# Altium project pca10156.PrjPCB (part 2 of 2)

## Sheet pca10156_sheet7_connectors.SchDoc: =BoardTitle+' - Connectors'
size A3; Organization: Nordic Semiconductor; DocumentNumber: 7; Revision: 0.9.1; SheetNumber: 7; SheetTotal: 7; Author: STL1; CompanyName: Nordic Semiconductor; DrawnBy: STL1; DocumentSize: A4

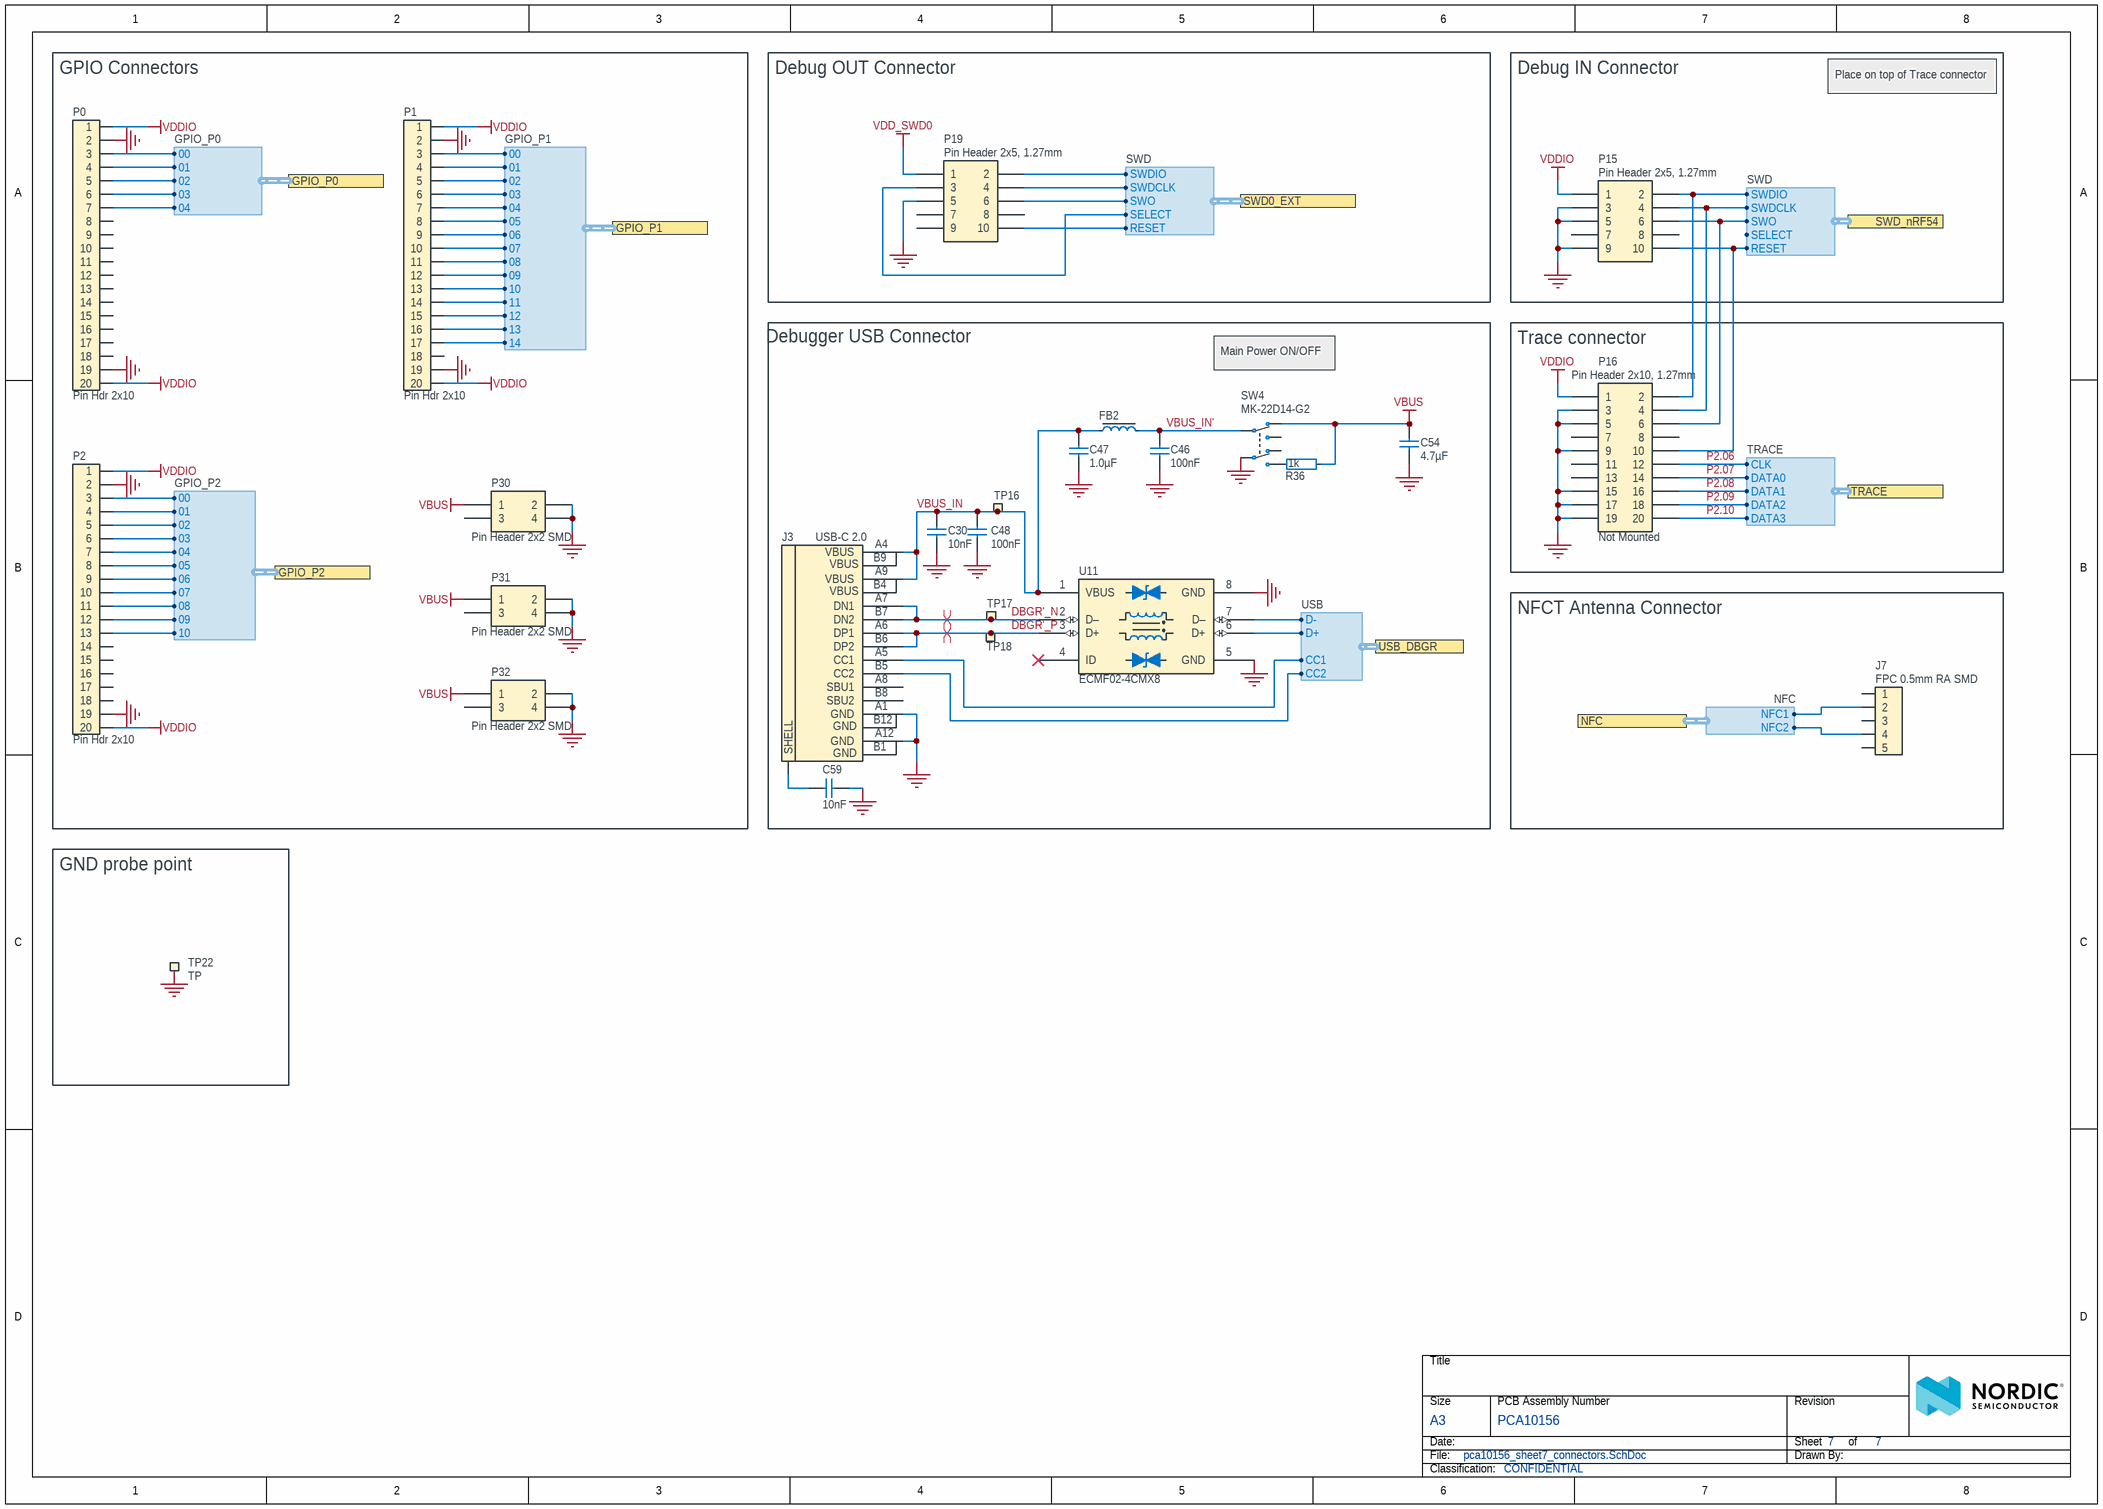
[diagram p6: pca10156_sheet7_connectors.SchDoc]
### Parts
C30  10nF  [CAPC0603X03L_C]
C46  100nF  [CAPC0603X03L_C]
C47  1.0µF  [CAPC1005X04L]
C48  100nF  [CAPC0603X03L_C]
C54  4.7µF  [CAPC1608X06L]
C59  10nF  [CAPC1608X06L]
FB2  120R/0.55A  [INDC1005X04L]  (value not drawn)
J3  USB-C 2.0  [SD-80259-001]
J7  FPC 0.5mm RA SMD  [FPC_05P-0.5mm-RA-SMD]
P0  Pin Hdr 2x10  [HDR_2x10-SMD]
P1  Pin Hdr 2x10  [HDR_2x10-SMD]
P2  Pin Hdr 2x10  [HDR_2x10-SMD]
P15  Pin Header 2x5, 1.27mm  [HDR_2x5-SMD-1.27mm-K]
P16  Pin Header 2x10, 1.27mm  Assembly: Not Mounted  [HDR_2x10-SMD-1.27mm-NC]
P19  Pin Header 2x5, 1.27mm  [HDR_2x5-SMD-1.27mm-K]
P30  Pin Header 2x2 SMD  [HDR_2x2-SMD]
P31  Pin Header 2x2 SMD  [HDR_2x2-SMD]
P32  Pin Header 2x2 SMD  [HDR_2x2-SMD]
R36  1k  [RESC0603X03L_C]
SW4  MK-22D14-G2  [MK-22D14-G2]
TP16  Ø1.5mm,SMD  [TP_SMD_D1.5mm]  (value not drawn)  (no BOM)
TP17  Ø1.5mm,SMD  [TP_SMD_D1.5mm]  (value not drawn)  (no BOM)
TP18  Ø1.5mm,SMD  [TP_SMD_D1.5mm]  (value not drawn)  (no BOM)
TP22  TP  [S1751]
U11  ECMF02-4CMX8  [UFDFN50P120X250X55-8N]

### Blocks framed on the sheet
GPIO Connectors: P0-P2 P30-P32
Debug OUT Connector: P19
Debug IN Connector: P15
Debugger USB Connector: C30 C46-C48 C54 C59 FB2 J3 R36 SW4 TP16-TP18 U11
Trace connector: P16
NFCT Antenna Connector: J7
GND probe point: TP22

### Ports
GPIO_P0 (harness GPIO_P0), GPIO_P1 (harness GPIO_P1), GPIO_P2 (harness GPIO_P2), NFC (harness NFC), SWD0_EXT (harness SWD), SWD_nRF54 (harness SWD), TRACE (harness TRACE), USB_DBGR (harness USB)

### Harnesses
USB: D+, D-, CC1, CC2
SWD: SWDIO, SWDCLK, SWO, RESET, SELECT
NFC: NFC2, NFC1
GPIO_P1: 00, 01, 02, 03, 04, 05, 06, 07, 08, 09, 10, 11, 12, 13, 14
GPIO_P2: 00, 01, 02, 03, 04, 05, 06, 07, 08, 09, 10
TRACE: CLK, DATA0, DATA1, DATA3, DATA2
GPIO_P0: 02, 03, 04, 00, 01

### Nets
GND: C30.2 C46.1 C47.1 C48.1 C54.2 C59.2 J3.A1(GND) J3.A12(GND) P0.2 P0.19 P1.2 P1.19 P2.2 P2.19 P15.3 P15.5 P15.9 P16.3 P16.5 P16.9 P16.15 P16.17 P16.19 P19.5 P30.2 P30.4 P31.2 P31.4 P32.2 P32.4 SW4.5(COM-2) TP22.1 U11.5(GND) U11.8(GND)
VBUS: C54.1 P30.1 P31.1 P32.1 R36.2 SW4.3(N.C-1)
VDD_SWD0: P19.1
VDDIO: P0.1 P0.20 P1.1 P1.20 P2.1 P2.20 P15.1 P16.1
DBGR'_N: J3.A7(DN1) J3.B7(DN2) TP17.1 U11.2(D–)
DBGR'_P: J3.A6(DP1) J3.B6(DP2) TP18.1 U11.3(D+)
DBGR_N: U11.7(D–) ; port USB_DBGR.D-
DBGR_P: U11.6(D+) ; port USB_DBGR.D+
NFC1: J7.2 ; port NFC.NFC1
NFC2: J7.4 ; port NFC.NFC2
nRF54L15_RESET: P15.10 P16.10 ; port SWD_nRF54.RESET
P0.00: P0.3 ; port GPIO_P0.00
P0.01: P0.4 ; port GPIO_P0.01
P0.02: P0.5 ; port GPIO_P0.02
P0.03: P0.6 ; port GPIO_P0.03
P0.04: P0.7 ; port GPIO_P0.04
P1.00: P1.3 ; port GPIO_P1.00
P1.01: P1.4 ; port GPIO_P1.01
P1.04: P1.7 ; port GPIO_P1.04
P1.05: P1.8 ; port GPIO_P1.05
P1.06: P1.9 ; port GPIO_P1.06
P1.07: P1.10 ; port GPIO_P1.07
P1.08: P1.11 ; port GPIO_P1.08
P1.09: P1.12 ; port GPIO_P1.09
P1.10: P1.13 ; port GPIO_P1.10
P1.11: P1.14 ; port GPIO_P1.11
P1.12: P1.15 ; port GPIO_P1.12
P1.13: P1.16 ; port GPIO_P1.13
P1.14: P1.17 ; port GPIO_P1.14
P2.06: P2.9 P16.12 ; port GPIO_P2.06, port TRACE.CLK
P2.07: P2.10 P15.6 P16.6 P16.14 ; port SWD_nRF54.SWO, port GPIO_P2.07, port TRACE.DATA0
P2.08: P2.11 P16.16 ; port GPIO_P2.08, port TRACE.DATA1
P2.09: P2.12 P16.18 ; port GPIO_P2.09, port TRACE.DATA2
P2.10: P2.13 P16.20 ; port GPIO_P2.10, port TRACE.DATA3
SWD0_CLK_EXT: P19.4 ; port SWD0_EXT.SWDCLK
SWD0_IO_EXT: P19.2 ; port SWD0_EXT.SWDIO
SWD0_RESET_EXT: P19.10 ; port SWD0_EXT.RESET
SWD0_SEL: P19.3 ; port SWD0_EXT.SELECT
SWD0_SWO_EXT: P19.6 ; port SWD0_EXT.SWO
SWDCLK: P15.4 P16.4 ; port SWD_nRF54.SWDCLK
SWDIO: P15.2 P16.2 ; port SWD_nRF54.SWDIO
VBUS_IN: C30.1 C47.2 C48.2 FB2.1 J3.A4(VBUS) J3.A9(VBUS) TP16.1 U11.1(VBUS)
VBUS_IN': C46.2 FB2.2 SW4.2(COM-1)
NetC59_1: C59.1 J3.SHLD(SHELL)
NetJ3_A5: J3.A5(CC1) ; port USB_DBGR.CC1
NetJ3_B5: J3.B5(CC2) ; port USB_DBGR.CC2
NetP1_5: P1.5 ; port GPIO_P1.02
NetP1_6: P1.6 ; port GPIO_P1.03
NetP2_3: P2.3 ; port GPIO_P2.00
NetP2_4: P2.4 ; port GPIO_P2.01
NetP2_5: P2.5 ; port GPIO_P2.02
NetP2_6: P2.6 ; port GPIO_P2.03
NetP2_7: P2.7 ; port GPIO_P2.04
NetP2_8: P2.8 ; port GPIO_P2.05
NetR36_1: R36.1 SW4.4(N.O-2)

Not connected (* = marked no-connect by the designer): J3 A8(SBU1) B8(SBU2); J7 1 3 5; P0 8 9 10 11 12 13 14 15 16 17 18; P1 18; P2 14 15 16 17 18; P15 7 8; P16 7 8 11 13; P19 7 8 9; P30 3; P31 3; P32 3; SW4 1(N.O-1) 6(N.C-2); U11 4(ID)*

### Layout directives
differential pair; differential pair class IMCU; net class IMCU_USB: DBGR'_N, DBGR'_P

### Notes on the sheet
- Place on top of Trace connector
- Main Power ON/OFF

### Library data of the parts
C30 = C0201-10n: Capacitor, X7R, ±10%; Manufacturer: N.A.; Part number IPS: 00000003480; Part number Norautron: 26621779; Part number NEMS: 100200067; Note: 10V; Pad Count: 2; Component Status: Active
C46 C48 = C0201-100n: Capacitor, X5R, ±10%; Manufacturer: N.A.; Part number IPS: 00000001248, 00000002505; Part number Norautron: 262071862; Part number NEMS: 100200078; Note: 16V; Pad Count: 2; Component Status: Active
C47 = C0402-1µ0-16V-X5R: Capacitor, Ceramic, X5R, ±10%, 16V; Manufacturer: Murata; Manufacturer Part Number: GRT155R61C105KE01D; Part number NEMS: 100200452; Component Status: Active; Pad Count: 2; Artikkelnr Noca: N.A.
C54 = C0603-4µ7-10V-X7S: Capacitor, X7S, ±10%, 10V; Manufacturer: N.A.; Part number IPS: 00000001779; Part number NEMS: 100200351; Pad Count: 2; Artikkelnr Noca: 20030013; Component Status: Active
C59 = C0603-10n-100V-X7R: Capacitor, X7R, ±10%, 100V; Manufacturer: Murata; Manufacturer Part Number: GCM188R72A103KA37D; Part number NEMS: 100200349; Component Status: Active; Pad Count: 2; Artikkelnr Noca: N.A.
FB2 = FB0402-120R@100M-500mA: Ferrite Bead, 120 Ohm @ 100MHz, 500mA, 250 mOhm Max; Manufacturer: Murata; Manufacturer Part Number: BLM15AG121SN1D; Part number IPS: 00000009954; Part number Norautron: 265230631; Part number NEMS: 100300099; Note: Chip EMIFIL Inductor Type Chip Ferrite Bead; Artikkelnr Noca: 33029317; Pad Count: 2; Component Status: Active
J3 = SD-80259-1021: USB-C Receptacle, 16 Pin, USB 2.0; Manufacturer: Bellweather Electronic Corp.; Part number NEMS: 100500830; Component Status: Active; Pad Count: 16; Note: N.A.; System: Connector
J7 = FPC_05P-0.5mm-RA-SMD: 0.5mm FPC, 5P,Right Angle SMT,Double Contact,H=1.2mm,White, Tin plated; Manufacturer: WCON; Manufacturer Part Number: 5141-05RZDNWR03; Part number NEMS: 100500528; Note: (Replaced 5141-05RZDNWR02); Artikkelnr Noca: N.A.; Pad Count: 7; Component Status: Active; System: Connector
P0-P2 = Pin Header 2x10 SMD, 2.54mm: Pin Header 2x10, 2.54mm (100mil) SMD; Manufacturer: WCON; Manufacturer Part Number: 1125-1210S0M116CR09; Part number NEMS: 100500738; Pad Count: 20; Artikkelnr Noca: N.A.; Component Status: Active; System: Connector
P15 P19 = Pin Header 2x5 SMD, 1.27mm, KS: Pin Header 2x5, 1.27mm (50mil), SMD, Keying Shroud; Manufacturer: WCON; Manufacturer Part Number: 3132-10MS0BK00R5; Part number NEMS: 100500261; Note: (Replaced 3132-10MS0BK00R1); Artikkelnr Noca: N.A.; Pad Count: 10; Component Status: Active; System: Connector
P16 = Pin Header 2x10 SMD, 1.27mm, KS, N.C.: Pin Header 2x10, 1.27mm (50mil), SMD, Keying Shroud; Manufacturer: WCON; Manufacturer Part Number: 3132-20MS0BK00R1; Part number NEMS: 100500279; Note: N.A.; Pad Count: 20; Component Status: Active; System: Connector
P30-P32 = Pin Header 2x2 SMD: Pin Header 2x2, SMD, 2.54mm (100mil); Manufacturer: WCON; Manufacturer Part Number: 1125-1202S0M116CR03; Part number NEMS: 100500770; Component Status: Active; Pad Count: 4; Note: N.A.; System: Connector
R36 = R0201-1k0: Resistor, ±1%, 0.05W; Manufacturer: N.A.; Part number IPS: 00000005786; Part number NEMS: 100100043; Component Status: Active; Pad Count: 2; Note: Chip Res 1%
SW4 = MK-22D14-G2: Slide Switch DPDT; Manufacturer: HUA-JIE CORP.; Part number NEMS: 101500131; Note: N.A.; Pad Count: 6; Component Status: Active
TP16-TP18 = TP_SMD_Ø1.5MM: 1.5mm circular SMD testpad; Manufacturer: Nordic Semiconductor; Manufacturer Part Number: N.A.; Part number NEMS: 100500477; Pad Count: 1; Component Status: Active
TP22 = TP - S1751-46R: PC TEST POINT TIN SMD L; Manufacturer: Harwin; Part number NEMS: 100500525; Component Status: Active; Pad Count: 1; Note: N.A.
U11 = ECMF02-4CMX8: 2 Line Common mode filter with ESD protection for USB 2.0 interface; Manufacturer: STMicroelectronics; Part number NEMS: 100800034; Component Status: Active; Pad Count: 8; Note: N.A.

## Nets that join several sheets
GND: pca10156_sheet2_nRF54L15 (22 pins), pca10156_sheet3_debugger (31 pins), pca10156_sheet4_level_shifters (13 pins), pca10156_sheet5_misc (18 pins), pca10156_sheet6_power_supply (20 pins), pca10156_sheet7_connectors (34 pins)
P3V3: pca10156_sheet4_level_shifters (U4.14 U5.14 U6.14), pca10156_sheet6_power_supply (6 pins)
VBUS: pca10156_sheet3_debugger (J4.5 R5.2), pca10156_sheet6_power_supply (6 pins), pca10156_sheet7_connectors (6 pins)
VBUSOUT: pca10156_sheet3_debugger (C42.1 U2.A5), pca10156_sheet6_power_supply (U10.22)
VDD_DBGR: pca10156_sheet3_debugger (31 pins), pca10156_sheet4_level_shifters (10 pins), pca10156_sheet5_misc (R23.2)
VDD_nRF: pca10156_sheet2_nRF54L15 (11 pins), pca10156_sheet5_misc (SB10.1), pca10156_sheet6_power_supply (R28.1)
VDD_SWD0: pca10156_sheet4_level_shifters (5 pins), pca10156_sheet7_connectors (P19.1)
VDDIO: pca10156_sheet3_debugger (NT4.2), pca10156_sheet5_misc (SB9.1), pca10156_sheet6_power_supply (5 pins), pca10156_sheet7_connectors (8 pins)
VDDM: pca10156_sheet3_debugger (R29.2), pca10156_sheet6_power_supply (C58.1 FB3.2 P6.3 R24.2)
VDDM_nRF: pca10156_sheet2_nRF54L15 (C3.2 P4.1 U1.48), pca10156_sheet6_power_supply (P6.2 R24.1)
DBGR_BUTTON: pca10156_sheet1_connections (SB2.2), pca10156_sheet3_debugger (U2.AL27)
DBGR_N: pca10156_sheet3_debugger (U2.B4), pca10156_sheet7_connectors (U11.7)
DBGR_P: pca10156_sheet3_debugger (U2.B2), pca10156_sheet7_connectors (U11.6)
LED_PWR_CTRL: pca10156_sheet3_debugger (U2.A17), pca10156_sheet6_power_supply (U10.8)
NetJ3_A5: pca10156_sheet6_power_supply (U10.23), pca10156_sheet7_connectors (J3.A5)
NetJ3_B5: pca10156_sheet6_power_supply (U10.24), pca10156_sheet7_connectors (J3.B5)
NetP1_5: pca10156_sheet2_nRF54L15 (R33.2), pca10156_sheet7_connectors (P1.5)
NetP1_6: pca10156_sheet2_nRF54L15 (R34.2), pca10156_sheet7_connectors (P1.6)
NetP2_3: pca10156_sheet2_nRF54L15 (SB17.1), pca10156_sheet7_connectors (P2.3)
NetP2_4: pca10156_sheet2_nRF54L15 (SB18.1), pca10156_sheet7_connectors (P2.4)
NetP2_5: pca10156_sheet2_nRF54L15 (SB19.1), pca10156_sheet7_connectors (P2.5)
NetP2_6: pca10156_sheet2_nRF54L15 (SB20.1), pca10156_sheet7_connectors (P2.6)
NetP2_7: pca10156_sheet2_nRF54L15 (SB21.1), pca10156_sheet7_connectors (P2.7)
NetP2_8: pca10156_sheet2_nRF54L15 (SB22.1), pca10156_sheet7_connectors (P2.8)
NetR1_2: pca10156_sheet5_misc (R1.2 R2.2 R19.2 R20.2), pca10156_sheet6_power_supply (R54.1 U10.31)
NetR4_2: pca10156_sheet3_debugger (R4.2), pca10156_sheet4_level_shifters (U6.16)
NetR9_2: pca10156_sheet3_debugger (R9.2), pca10156_sheet4_level_shifters (U6.4)
NetR37_2: pca10156_sheet3_debugger (R37.2), pca10156_sheet4_level_shifters (U6.12)
NetR38_2: pca10156_sheet3_debugger (R38.2), pca10156_sheet4_level_shifters (U6.8)
NetSB1_2: pca10156_sheet1_connections (SB1.2 SB2.1), pca10156_sheet5_misc (SB8.1 SW1.2)
NetSB11_2: pca10156_sheet2_nRF54L15 (SB11.2), pca10156_sheet5_misc (U9.1)
NetSB12_2: pca10156_sheet2_nRF54L15 (SB12.2), pca10156_sheet5_misc (U9.6)
NetSB13_2: pca10156_sheet2_nRF54L15 (SB13.2), pca10156_sheet5_misc (U9.5)
NetSB14_2: pca10156_sheet2_nRF54L15 (SB14.2), pca10156_sheet5_misc (U9.2)
NetSB15_2: pca10156_sheet2_nRF54L15 (SB15.2), pca10156_sheet5_misc (U9.3)
NetSB16_2: pca10156_sheet2_nRF54L15 (SB16.2), pca10156_sheet5_misc (U9.7)
NFC1: pca10156_sheet5_misc (C17.1 R21.2), pca10156_sheet7_connectors (J7.2)
NFC2: pca10156_sheet5_misc (C19.2 R22.2), pca10156_sheet7_connectors (J7.4)
nRF54L15_RESET: pca10156_sheet1_connections (SB1.1), pca10156_sheet2_nRF54L15 (R3.2), pca10156_sheet4_level_shifters (U6.7), pca10156_sheet7_connectors (P15.10 P16.10)
P0.00: pca10156_sheet2_nRF54L15 (U1.23), pca10156_sheet4_level_shifters (U4.3), pca10156_sheet7_connectors (P0.3)
P0.01: pca10156_sheet2_nRF54L15 (U1.24), pca10156_sheet4_level_shifters (U4.15), pca10156_sheet7_connectors (P0.4)
P0.02: pca10156_sheet2_nRF54L15 (U1.27), pca10156_sheet4_level_shifters (U4.11), pca10156_sheet7_connectors (P0.5)
P0.03: pca10156_sheet2_nRF54L15 (U1.28), pca10156_sheet4_level_shifters (U4.7), pca10156_sheet7_connectors (P0.6)
P0.04: pca10156_sheet2_nRF54L15 (U1.29), pca10156_sheet5_misc (SW6.2), pca10156_sheet7_connectors (P0.7)
P1.00: pca10156_sheet2_nRF54L15 (SB5.2), pca10156_sheet7_connectors (P1.3)
P1.01: pca10156_sheet2_nRF54L15 (SB6.2), pca10156_sheet7_connectors (P1.4)
P1.02/NFC1: pca10156_sheet2_nRF54L15 (R33.1 U1.3), pca10156_sheet5_misc (R21.1)
P1.03/NFC2: pca10156_sheet2_nRF54L15 (R34.1 U1.4), pca10156_sheet5_misc (R22.1)
P1.04: pca10156_sheet2_nRF54L15 (U1.5), pca10156_sheet4_level_shifters (U5.3), pca10156_sheet7_connectors (P1.7)
P1.05: pca10156_sheet2_nRF54L15 (U1.6), pca10156_sheet4_level_shifters (U5.15), pca10156_sheet7_connectors (P1.8)
P1.06: pca10156_sheet2_nRF54L15 (U1.7), pca10156_sheet4_level_shifters (U5.11), pca10156_sheet7_connectors (P1.9)
P1.07: pca10156_sheet2_nRF54L15 (U1.8), pca10156_sheet4_level_shifters (U5.7), pca10156_sheet7_connectors (P1.10)
P1.08: pca10156_sheet2_nRF54L15 (C41.2 U1.9), pca10156_sheet5_misc (SW5.2), pca10156_sheet7_connectors (P1.11)
P1.09: pca10156_sheet2_nRF54L15 (U1.37), pca10156_sheet5_misc (SW3.2), pca10156_sheet7_connectors (P1.12)
P1.10: pca10156_sheet2_nRF54L15 (U1.38), pca10156_sheet5_misc (Q3.2 R11.1), pca10156_sheet7_connectors (P1.13)
P1.11: pca10156_sheet2_nRF54L15 (U1.39), pca10156_sheet7_connectors (P1.14)
P1.12: pca10156_sheet2_nRF54L15 (U1.40), pca10156_sheet7_connectors (P1.15)
P1.13: pca10156_sheet2_nRF54L15 (U1.41), pca10156_sheet5_misc (SW2.2), pca10156_sheet7_connectors (P1.16)
P1.14: pca10156_sheet2_nRF54L15 (U1.42), pca10156_sheet5_misc (Q3.5 R27.1), pca10156_sheet7_connectors (P1.17)
P2.06: pca10156_sheet2_nRF54L15 (U1.17), pca10156_sheet7_connectors (P2.9 P16.12)
P2.07: pca10156_sheet2_nRF54L15 (U1.18), pca10156_sheet4_level_shifters (SB24.2), pca10156_sheet5_misc (Q2.5 R12.1), pca10156_sheet7_connectors (P2.10 P15.6 P16.6 P16.14)
P2.08: pca10156_sheet2_nRF54L15 (U1.19), pca10156_sheet7_connectors (P2.11 P16.16)
P2.09: pca10156_sheet2_nRF54L15 (U1.20), pca10156_sheet5_misc (Q2.2 R10.1), pca10156_sheet7_connectors (P2.12 P16.18)
P2.10: pca10156_sheet2_nRF54L15 (U1.21), pca10156_sheet7_connectors (P2.13 P16.20)
SWD0_CLK: pca10156_sheet3_debugger (U2.B18), pca10156_sheet4_level_shifters (U7.3)
SWD0_CLK_EXT: pca10156_sheet4_level_shifters (U7.6), pca10156_sheet7_connectors (P19.4)
SWD0_IO: pca10156_sheet3_debugger (U2.B16), pca10156_sheet4_level_shifters (U7.2)
SWD0_IO_EXT: pca10156_sheet4_level_shifters (U7.7), pca10156_sheet7_connectors (P19.2)
SWD0_RESET: pca10156_sheet3_debugger (U2.B22), pca10156_sheet4_level_shifters (U8.3)
SWD0_RESET_EXT: pca10156_sheet4_level_shifters (U8.6), pca10156_sheet7_connectors (P19.10)
SWD0_SEL: pca10156_sheet3_debugger (U2.B24), pca10156_sheet4_level_shifters (Q1.5), pca10156_sheet7_connectors (P19.3)
SWD0_SWO: pca10156_sheet3_debugger (U2.B20), pca10156_sheet4_level_shifters (U8.2)
SWD0_SWO_EXT: pca10156_sheet4_level_shifters (U8.7), pca10156_sheet7_connectors (P19.6)
SWD3_CTRL: pca10156_sheet3_debugger (U2.AB2), pca10156_sheet4_level_shifters (R17.2 U6.2 U6.10)
SWDCLK: pca10156_sheet2_nRF54L15 (U1.26), pca10156_sheet4_level_shifters (U6.3), pca10156_sheet7_connectors (P15.4 P16.4)
SWDIO: pca10156_sheet2_nRF54L15 (U1.25), pca10156_sheet4_level_shifters (U6.15), pca10156_sheet7_connectors (P15.2 P16.2)
TWI0_SCL: pca10156_sheet3_debugger (U2.AF2), pca10156_sheet6_power_supply (U10.14)
TWI0_SDA: pca10156_sheet3_debugger (U2.AE1), pca10156_sheet6_power_supply (U10.13)
UART0_CTRL: pca10156_sheet3_debugger (U2.R31), pca10156_sheet4_level_shifters (R13.2 U4.2)
UART0_CTS: pca10156_sheet3_debugger (U2.AL9), pca10156_sheet4_level_shifters (R55.1 U4.12)
UART0_HWFC: pca10156_sheet3_debugger (U2.AK16), pca10156_sheet4_level_shifters (R14.2 U4.10)
UART0_RTS: pca10156_sheet3_debugger (U2.AL5), pca10156_sheet4_level_shifters (U4.8)
UART0_RxD: pca10156_sheet3_debugger (U2.AL19), pca10156_sheet4_level_shifters (U4.4)
UART0_TxD: pca10156_sheet3_debugger (U2.U31), pca10156_sheet4_level_shifters (U4.16)
UART1_CTRL: pca10156_sheet3_debugger (U2.AK18), pca10156_sheet4_level_shifters (R15.2 U5.2)
UART1_CTS: pca10156_sheet3_debugger (U2.AL15), pca10156_sheet4_level_shifters (R56.1 U5.12)
UART1_HWFC: pca10156_sheet3_debugger (U2.AK20), pca10156_sheet4_level_shifters (R16.2 U5.10)
UART1_RTS: pca10156_sheet3_debugger (U2.AL13), pca10156_sheet4_level_shifters (U5.8)
UART1_RxD: pca10156_sheet3_debugger (U2.AL21), pca10156_sheet4_level_shifters (U5.4)
UART1_TxD: pca10156_sheet3_debugger (U2.AL23), pca10156_sheet4_level_shifters (U5.16)

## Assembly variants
Release: not fitted C41 C50 C51 C56 C59 P4 P16 R24 R29 R30 R33 R34 R54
